VERSION 5.8 ;
BUSBITCHARS "[]" ;
DIVIDERCHAR "/" ;
UNITS
    DATABASE MICRONS 1000 ;
END UNITS

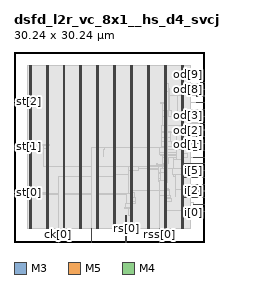
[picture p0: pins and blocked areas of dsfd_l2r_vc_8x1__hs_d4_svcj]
MACRO dsfd_l2r_vc_8x1__hs_d4_svcj
  FOREIGN dsfd_l2r_vc_8x1__hs_d4_svcj 0 0 ;
  CLASS BLOCK ;
  SIZE 30.24 BY 30.24 ;
  PIN ck[0]
    DIRECTION INPUT ;
    USE SIGNAL ;
    PORT
      LAYER M3 ;
        RECT  7.02 0 7.038 0.144 ;
    END
    PORT
      LAYER M3 ;
        RECT  7.02 0.108 7.038 0.52 ;
    END
  END ck[0]
  PIN cks[0]
    DIRECTION INPUT ;
    USE SIGNAL ;
    PORT
      LAYER M5 ;
        RECT  12.384 0 12.408 0.192 ;
    END
    PORT
      LAYER M5 ;
        RECT  12.384 0.144 12.408 2.137 ;
    END
  END cks[0]
  PIN fo[0]
    DIRECTION OUTPUT ;
    USE SIGNAL ;
    PORT
      LAYER M4 ;
        RECT  30.048 4.896 30.24 4.92 ;
    END
    PORT
      LAYER M4 ;
        RECT  27.004 4.896 30.06 4.92 ;
    END
  END fo[0]
  PIN i[0]
    DIRECTION INPUT ;
    USE SIGNAL ;
    PORT
      LAYER M4 ;
        RECT  30.048 5.952 30.24 5.976 ;
    END
    PORT
      LAYER M4 ;
        RECT  28.501 5.952 30.06 5.976 ;
    END
  END i[0]
  PIN i[1]
    DIRECTION INPUT ;
    USE SIGNAL ;
    PORT
      LAYER M4 ;
        RECT  30.048 7.056 30.24 7.08 ;
    END
    PORT
      LAYER M4 ;
        RECT  27.004 7.056 30.06 7.08 ;
    END
  END i[1]
  PIN i[2]
    DIRECTION INPUT ;
    USE SIGNAL ;
    PORT
      LAYER M4 ;
        RECT  30.048 8.112 30.24 8.136 ;
    END
    PORT
      LAYER M4 ;
        RECT  28.501 8.112 30.06 8.136 ;
    END
  END i[2]
  PIN i[3]
    DIRECTION INPUT ;
    USE SIGNAL ;
    PORT
      LAYER M4 ;
        RECT  30.048 9.168 30.24 9.192 ;
    END
    PORT
      LAYER M4 ;
        RECT  28.501 9.168 30.06 9.192 ;
    END
  END i[3]
  PIN i[4]
    DIRECTION INPUT ;
    USE SIGNAL ;
    PORT
      LAYER M4 ;
        RECT  30.048 10.272 30.24 10.296 ;
    END
    PORT
      LAYER M4 ;
        RECT  27.004 10.272 30.06 10.296 ;
    END
  END i[4]
  PIN i[5]
    DIRECTION INPUT ;
    USE SIGNAL ;
    PORT
      LAYER M4 ;
        RECT  30.048 11.376 30.24 11.4 ;
    END
    PORT
      LAYER M4 ;
        RECT  29.653 11.376 30.06 11.4 ;
    END
  END i[5]
  PIN i[6]
    DIRECTION INPUT ;
    USE SIGNAL ;
    PORT
      LAYER M4 ;
        RECT  30.048 12.432 30.24 12.456 ;
    END
    PORT
      LAYER M4 ;
        RECT  27.004 12.432 30.06 12.456 ;
    END
  END i[6]
  PIN i[7]
    DIRECTION INPUT ;
    USE SIGNAL ;
    PORT
      LAYER M4 ;
        RECT  30.048 13.488 30.24 13.512 ;
    END
    PORT
      LAYER M4 ;
        RECT  28.501 13.488 30.06 13.512 ;
    END
  END i[7]
  PIN i[8]
    DIRECTION INPUT ;
    USE SIGNAL ;
    PORT
      LAYER M4 ;
        RECT  30.048 14.592 30.24 14.616 ;
    END
    PORT
      LAYER M4 ;
        RECT  28.501 14.592 30.06 14.616 ;
    END
  END i[8]
  PIN od[0]
    DIRECTION OUTPUT ;
    USE SIGNAL ;
    PORT
      LAYER M4 ;
        RECT  30.048 15.648 30.24 15.672 ;
    END
    PORT
      LAYER M4 ;
        RECT  28.501 15.648 30.06 15.672 ;
    END
  END od[0]
  PIN od[1]
    DIRECTION OUTPUT ;
    USE SIGNAL ;
    PORT
      LAYER M4 ;
        RECT  30.048 16.752 30.24 16.776 ;
    END
    PORT
      LAYER M4 ;
        RECT  29.041 16.752 30.06 16.776 ;
    END
  END od[1]
  PIN od[2]
    DIRECTION OUTPUT ;
    USE SIGNAL ;
    PORT
      LAYER M4 ;
        RECT  30.048 17.808 30.24 17.832 ;
    END
    PORT
      LAYER M4 ;
        RECT  29.653 17.808 30.06 17.832 ;
    END
  END od[2]
  PIN od[3]
    DIRECTION OUTPUT ;
    USE SIGNAL ;
    PORT
      LAYER M4 ;
        RECT  30.048 18.912 30.24 18.936 ;
    END
    PORT
      LAYER M4 ;
        RECT  29.617 18.912 30.06 18.936 ;
    END
  END od[3]
  PIN od[4]
    DIRECTION OUTPUT ;
    USE SIGNAL ;
    PORT
      LAYER M4 ;
        RECT  30.048 19.968 30.24 19.992 ;
    END
    PORT
      LAYER M4 ;
        RECT  29.041 19.968 30.06 19.992 ;
    END
  END od[4]
  PIN od[5]
    DIRECTION OUTPUT ;
    USE SIGNAL ;
    PORT
      LAYER M4 ;
        RECT  30.048 21.072 30.24 21.096 ;
    END
    PORT
      LAYER M4 ;
        RECT  29.617 21.072 30.06 21.096 ;
    END
  END od[5]
  PIN od[6]
    DIRECTION OUTPUT ;
    USE SIGNAL ;
    PORT
      LAYER M4 ;
        RECT  30.048 22.128 30.24 22.152 ;
    END
    PORT
      LAYER M4 ;
        RECT  29.077 22.128 30.06 22.152 ;
    END
  END od[6]
  PIN od[7]
    DIRECTION OUTPUT ;
    USE SIGNAL ;
    PORT
      LAYER M4 ;
        RECT  30.048 23.232 30.24 23.256 ;
    END
    PORT
      LAYER M4 ;
        RECT  29.041 23.232 30.06 23.256 ;
    END
  END od[7]
  PIN od[8]
    DIRECTION OUTPUT ;
    USE SIGNAL ;
    PORT
      LAYER M4 ;
        RECT  30.048 24.288 30.24 24.312 ;
    END
    PORT
      LAYER M4 ;
        RECT  29.653 24.288 30.06 24.312 ;
    END
  END od[8]
  PIN od[9]
    DIRECTION OUTPUT ;
    USE SIGNAL ;
    PORT
      LAYER M4 ;
        RECT  30.048 25.392 30.24 25.416 ;
    END
    PORT
      LAYER M4 ;
        RECT  29.653 25.392 30.06 25.416 ;
    END
  END od[9]
  PIN rs[0]
    DIRECTION INPUT ;
    USE SIGNAL ;
    PORT
      LAYER M3 ;
        RECT  17.82 0 17.838 0.144 ;
    END
    PORT
      LAYER M3 ;
        RECT  17.82 0.108 17.838 4.145 ;
    END
  END rs[0]
  PIN rss[0]
    DIRECTION INPUT ;
    USE SIGNAL ;
    PORT
      LAYER M5 ;
        RECT  23.184 0 23.208 0.192 ;
    END
    PORT
      LAYER M5 ;
        RECT  23.184 0.144 23.208 2.137 ;
    END
  END rss[0]
  PIN st[0]
    DIRECTION OUTPUT ;
    USE SIGNAL ;
    PORT
      LAYER M4 ;
        RECT  0 7.92 0.192 7.944 ;
    END
    PORT
      LAYER M4 ;
        RECT  0.156 7.92 2.408 7.944 ;
    END
  END st[0]
  PIN st[1]
    DIRECTION OUTPUT ;
    USE SIGNAL ;
    PORT
      LAYER M4 ;
        RECT  0 15.12 0.192 15.144 ;
    END
    PORT
      LAYER M4 ;
        RECT  0.156 15.12 2.408 15.144 ;
    END
  END st[1]
  PIN st[2]
    DIRECTION OUTPUT ;
    USE SIGNAL ;
    PORT
      LAYER M4 ;
        RECT  0 22.32 0.192 22.344 ;
    END
    PORT
      LAYER M4 ;
        RECT  0.156 22.32 0.245 22.344 ;
    END
  END st[2]
  PIN VDD
    DIRECTION INOUT ;
    USE POWER ;
    PORT
      LAYER M5 ;
        RECT  26.892 2.151 27.012 28.089 ;
        RECT  24.192 2.151 24.312 28.089 ;
        RECT  21.492 2.151 21.612 28.089 ;
        RECT  18.792 2.151 18.912 28.089 ;
        RECT  16.092 2.151 16.212 28.089 ;
        RECT  13.392 2.151 13.512 28.089 ;
        RECT  10.692 2.151 10.812 28.089 ;
        RECT  7.992 2.151 8.112 28.089 ;
        RECT  5.292 2.151 5.412 28.089 ;
        RECT  2.592 2.151 2.712 28.089 ;
    END
  END VDD
  PIN VSS
    DIRECTION INOUT ;
    USE GROUND ;
    PORT
      LAYER M5 ;
        RECT  26.7 2.137 26.82 28.103 ;
        RECT  24 2.137 24.12 28.103 ;
        RECT  21.3 2.137 21.42 28.103 ;
        RECT  18.6 2.137 18.72 28.103 ;
        RECT  15.9 2.137 16.02 28.103 ;
        RECT  13.2 2.137 13.32 28.103 ;
        RECT  10.5 2.137 10.62 28.103 ;
        RECT  7.8 2.137 7.92 28.103 ;
        RECT  5.1 2.137 5.22 28.103 ;
        RECT  2.4 2.137 2.52 28.103 ;
    END
  END VSS
  # OT_OBS_CLOSED layer=M5 d_um=1.536 added=0
  OBS
    LAYER RVTN ;
     RECT  2.16 2.16 28.08 2.295 ;
     RECT  2.16 2.565 28.08 2.835 ;
     RECT  2.16 3.105 28.08 3.375 ;
     RECT  2.16 3.645 28.08 3.915 ;
     RECT  2.16 4.185 28.08 4.455 ;
     RECT  2.16 4.725 28.08 4.995 ;
     RECT  2.16 5.265 28.08 5.535 ;
     RECT  2.16 5.805 28.08 6.075 ;
     RECT  2.16 6.345 28.08 6.615 ;
     RECT  2.16 6.885 28.08 7.155 ;
     RECT  2.16 7.425 28.08 7.695 ;
     RECT  2.16 7.965 28.08 8.235 ;
     RECT  2.16 8.505 28.08 8.775 ;
     RECT  2.16 9.045 28.08 9.315 ;
     RECT  2.16 9.585 28.08 9.855 ;
     RECT  2.16 10.125 28.08 10.395 ;
     RECT  2.16 10.665 28.08 10.935 ;
     RECT  2.16 11.205 28.08 11.475 ;
     RECT  2.16 11.745 28.08 12.015 ;
     RECT  2.16 12.285 28.08 12.555 ;
     RECT  2.16 12.825 28.08 13.095 ;
     RECT  2.16 13.365 28.08 13.635 ;
     RECT  2.16 13.905 28.08 14.175 ;
     RECT  2.16 14.445 28.08 14.715 ;
     RECT  2.16 14.985 28.08 15.255 ;
     RECT  2.16 15.525 28.08 15.795 ;
     RECT  2.16 16.065 28.08 16.335 ;
     RECT  2.16 16.605 28.08 16.875 ;
     RECT  2.16 17.145 28.08 17.415 ;
     RECT  2.16 17.685 28.08 17.955 ;
     RECT  2.16 18.225 28.08 18.495 ;
     RECT  2.16 18.765 28.08 19.035 ;
     RECT  2.16 19.305 28.08 19.575 ;
     RECT  2.16 19.845 28.08 20.115 ;
     RECT  2.16 20.385 28.08 20.655 ;
     RECT  2.16 20.925 28.08 21.195 ;
     RECT  2.16 21.465 28.08 21.735 ;
     RECT  2.16 22.005 28.08 22.275 ;
     RECT  2.16 22.545 28.08 22.815 ;
     RECT  2.16 23.085 28.08 23.355 ;
     RECT  2.16 23.625 28.08 23.895 ;
     RECT  2.16 24.165 28.08 24.435 ;
     RECT  2.16 24.705 28.08 24.975 ;
     RECT  2.16 25.245 28.08 25.515 ;
     RECT  2.16 25.785 28.08 26.055 ;
     RECT  2.16 26.325 28.08 26.595 ;
     RECT  2.16 26.865 28.08 27.135 ;
     RECT  2.16 27.405 28.08 27.675 ;
     RECT  2.16 27.945 28.08 28.08 ;
    LAYER RVTP ;
     RECT  2.16 2.295 28.08 2.565 ;
     RECT  2.16 2.835 28.08 3.105 ;
     RECT  2.16 3.375 28.08 3.645 ;
     RECT  2.16 3.915 28.08 4.185 ;
     RECT  2.16 4.455 28.08 4.725 ;
     RECT  2.16 4.995 28.08 5.265 ;
     RECT  2.16 5.535 28.08 5.805 ;
     RECT  2.16 6.075 28.08 6.345 ;
     RECT  2.16 6.615 28.08 6.885 ;
     RECT  2.16 7.155 28.08 7.425 ;
     RECT  2.16 7.695 28.08 7.965 ;
     RECT  2.16 8.235 28.08 8.505 ;
     RECT  2.16 8.775 28.08 9.045 ;
     RECT  2.16 9.315 28.08 9.585 ;
     RECT  2.16 9.855 28.08 10.125 ;
     RECT  2.16 10.395 28.08 10.665 ;
     RECT  2.16 10.935 28.08 11.205 ;
     RECT  2.16 11.475 28.08 11.745 ;
     RECT  2.16 12.015 28.08 12.285 ;
     RECT  2.16 12.555 28.08 12.825 ;
     RECT  2.16 13.095 28.08 13.365 ;
     RECT  2.16 13.635 28.08 13.905 ;
     RECT  2.16 14.175 28.08 14.445 ;
     RECT  2.16 14.715 28.08 14.985 ;
     RECT  2.16 15.255 28.08 15.525 ;
     RECT  2.16 15.795 28.08 16.065 ;
     RECT  2.16 16.335 28.08 16.605 ;
     RECT  2.16 16.875 28.08 17.145 ;
     RECT  2.16 17.415 28.08 17.685 ;
     RECT  2.16 17.955 28.08 18.225 ;
     RECT  2.16 18.495 28.08 18.765 ;
     RECT  2.16 19.035 28.08 19.305 ;
     RECT  2.16 19.575 28.08 19.845 ;
     RECT  2.16 20.115 28.08 20.385 ;
     RECT  2.16 20.655 28.08 20.925 ;
     RECT  2.16 21.195 28.08 21.465 ;
     RECT  2.16 21.735 28.08 22.005 ;
     RECT  2.16 22.275 28.08 22.545 ;
     RECT  2.16 22.815 28.08 23.085 ;
     RECT  2.16 23.355 28.08 23.625 ;
     RECT  2.16 23.895 28.08 24.165 ;
     RECT  2.16 24.435 28.08 24.705 ;
     RECT  2.16 24.975 28.08 25.245 ;
     RECT  2.16 25.515 28.08 25.785 ;
     RECT  2.16 26.055 28.08 26.325 ;
     RECT  2.16 26.595 28.08 26.865 ;
     RECT  2.16 27.135 28.08 27.405 ;
     RECT  2.16 27.675 28.08 27.945 ;
    LAYER M1 ;
     RECT  2.16 2.151 28.08 28.089 ;
    LAYER M2 ;
     RECT  0.211 22.176 2.16 22.194 ;
     RECT  6.943 0.531 7.043 0.549 ;
     RECT  2.16 2.151 28.08 28.089 ;
     RECT  28.08 6.318 28.535 6.336 ;
     RECT  28.08 8.208 28.535 8.226 ;
     RECT  28.08 9.09 28.535 9.108 ;
     RECT  28.08 13.41 28.535 13.428 ;
     RECT  28.08 14.958 28.535 15.624 ;
     RECT  28.08 16.776 29.075 16.794 ;
     RECT  28.08 20.016 29.075 20.034 ;
     RECT  28.08 23.256 29.075 23.274 ;
     RECT  28.08 22.176 29.111 22.194 ;
     RECT  28.08 18.936 29.651 18.954 ;
     RECT  28.08 21.096 29.651 21.114 ;
     RECT  28.08 11.52 29.687 11.538 ;
     RECT  28.08 17.586 29.687 17.604 ;
     RECT  28.08 24.372 29.687 24.39 ;
     RECT  28.08 25.146 29.687 25.164 ;
    LAYER M3 ;
     RECT  6.948 0.52 7.038 0.554 ;
     RECT  6.948 0.554 6.966 0.557 ;
     RECT  2.415 2.143 2.505 2.413 ;
     RECT  5.115 2.143 5.205 2.413 ;
     RECT  7.815 2.143 7.905 2.413 ;
     RECT  10.515 2.143 10.605 2.413 ;
     RECT  13.215 2.143 13.305 2.413 ;
     RECT  15.915 2.143 16.005 2.413 ;
     RECT  18.615 2.143 18.705 2.413 ;
     RECT  21.315 2.143 21.405 2.413 ;
     RECT  24.015 2.143 24.105 2.413 ;
     RECT  26.715 2.143 26.805 2.413 ;
     RECT  18.615 2.413 18.897 4.261 ;
     RECT  26.715 2.413 26.997 5.029 ;
     RECT  26.064 5.029 26.997 5.069 ;
     RECT  18.288 4.261 18.897 5.305 ;
     RECT  17.64 5.305 18.897 5.459 ;
     RECT  17.676 5.459 18.897 6.143 ;
     RECT  17.964 6.143 18.897 6.151 ;
     RECT  17.964 6.151 19.278 6.173 ;
     RECT  26.715 5.069 26.997 6.241 ;
     RECT  26.676 6.241 26.997 6.341 ;
     RECT  28.512 5.947 28.53 6.341 ;
     RECT  24.015 2.413 24.297 6.385 ;
     RECT  18.252 6.173 19.278 6.413 ;
     RECT  24.015 6.385 24.75 6.421 ;
     RECT  24.015 6.421 25.11 6.845 ;
     RECT  26.715 6.341 26.997 7.051 ;
     RECT  24.015 6.845 24.894 7.087 ;
     RECT  18.615 6.413 19.278 7.151 ;
     RECT  27.936 7.051 27.954 7.151 ;
     RECT  26.715 7.051 27.054 7.231 ;
     RECT  23.976 7.087 24.894 7.349 ;
     RECT  26.715 7.231 27.234 7.349 ;
     RECT  23.976 7.349 24.75 7.385 ;
     RECT  23.976 7.385 24.714 7.393 ;
     RECT  23.76 7.393 24.714 7.421 ;
     RECT  5.115 2.413 5.397 7.627 ;
     RECT  2.415 2.413 2.697 7.771 ;
     RECT  4.572 7.627 5.397 7.771 ;
     RECT  18.615 7.151 19.134 7.799 ;
     RECT  4.284 7.771 5.397 7.889 ;
     RECT  18.615 7.799 18.897 7.897 ;
     RECT  4.896 7.889 5.397 7.925 ;
     RECT  2.415 7.771 2.754 7.949 ;
     RECT  18.54 7.897 18.897 7.949 ;
     RECT  23.76 7.421 24.297 8.203 ;
     RECT  28.512 8.107 28.53 8.231 ;
     RECT  23.76 8.203 24.57 8.311 ;
     RECT  25.668 7.321 25.686 8.311 ;
     RECT  26.715 7.349 26.997 8.311 ;
     RECT  23.76 8.311 24.714 8.429 ;
     RECT  25.668 8.311 27.63 8.429 ;
     RECT  23.76 8.429 24.57 8.465 ;
     RECT  26.715 8.429 27.63 8.501 ;
     RECT  23.76 8.465 24.297 9.121 ;
     RECT  28.512 9.085 28.53 9.197 ;
     RECT  23.4 9.121 24.297 9.355 ;
     RECT  23.256 9.355 24.297 9.391 ;
     RECT  23.256 9.391 24.354 9.691 ;
     RECT  23.04 9.691 24.354 10.085 ;
     RECT  27.936 10.267 27.954 10.391 ;
     RECT  15.915 2.413 16.197 10.411 ;
     RECT  25.668 8.429 25.758 10.471 ;
     RECT  15.804 10.411 16.197 10.589 ;
     RECT  25.344 10.471 25.758 10.705 ;
     RECT  15.915 10.589 16.197 10.741 ;
     RECT  25.2 10.705 25.758 10.741 ;
     RECT  26.715 8.501 26.997 10.741 ;
     RECT  15.915 10.741 16.398 10.781 ;
     RECT  23.004 10.201 23.022 10.975 ;
     RECT  23.76 10.085 24.354 10.975 ;
     RECT  21.315 2.413 21.597 11.515 ;
     RECT  23.004 10.975 24.354 11.515 ;
     RECT  29.664 11.371 29.682 11.543 ;
     RECT  19.8 11.419 19.818 11.659 ;
     RECT  21.315 11.515 24.354 11.659 ;
     RECT  25.2 10.741 26.997 11.705 ;
     RECT  19.8 11.659 20.394 11.939 ;
     RECT  20.376 11.939 20.394 11.981 ;
     RECT  21.315 11.659 24.39 12.209 ;
     RECT  22.68 12.209 24.39 12.281 ;
     RECT  23.688 12.281 24.39 12.361 ;
     RECT  22.68 12.281 22.806 12.479 ;
     RECT  22.68 12.479 22.698 12.515 ;
     RECT  23.688 12.361 24.498 12.523 ;
     RECT  27.936 12.427 27.954 12.551 ;
     RECT  25.308 11.705 26.997 13.091 ;
     RECT  23.688 12.523 24.534 13.441 ;
     RECT  25.308 13.091 25.938 13.441 ;
     RECT  26.715 13.091 26.997 13.441 ;
     RECT  28.512 13.405 28.53 13.517 ;
     RECT  23.688 13.441 25.938 13.711 ;
     RECT  23.256 13.711 25.938 13.981 ;
     RECT  26.715 13.441 27.666 14.009 ;
     RECT  23.112 13.981 25.938 14.237 ;
     RECT  14.292 13.531 14.31 14.675 ;
     RECT  23.544 14.237 25.938 14.791 ;
     RECT  26.715 14.009 26.997 14.791 ;
     RECT  5.115 7.925 5.397 14.827 ;
     RECT  14.4 14.791 14.418 15.089 ;
     RECT  2.415 7.949 2.697 15.115 ;
     RECT  2.304 15.115 2.697 15.179 ;
     RECT  23.544 14.791 26.997 15.179 ;
     RECT  4.68 14.827 5.397 15.331 ;
     RECT  4.572 15.331 5.634 15.449 ;
     RECT  5.115 15.449 5.634 15.593 ;
     RECT  28.512 14.587 28.53 15.677 ;
     RECT  23.544 15.179 25.074 15.989 ;
     RECT  23.544 15.989 24.93 16.645 ;
     RECT  29.052 16.747 29.07 16.799 ;
     RECT  23.436 16.645 24.93 17.491 ;
     RECT  25.884 15.179 26.997 17.491 ;
     RECT  23.436 17.491 26.997 17.609 ;
     RECT  29.664 17.581 29.682 17.837 ;
     RECT  23.544 17.609 26.997 18.563 ;
     RECT  29.628 18.907 29.646 18.959 ;
     RECT  23.58 18.563 26.997 19.913 ;
     RECT  26.064 19.913 26.997 19.921 ;
     RECT  29.052 19.963 29.07 20.039 ;
     RECT  26.064 19.921 27.306 20.075 ;
     RECT  23.58 19.913 25.11 20.957 ;
     RECT  29.628 21.067 29.646 21.119 ;
     RECT  23.58 20.957 24.786 22.027 ;
     RECT  23.256 22.027 24.786 22.199 ;
     RECT  29.088 22.123 29.106 22.199 ;
     RECT  23.256 22.199 23.274 22.235 ;
     RECT  0.216 22.171 0.234 22.349 ;
     RECT  26.064 20.075 26.997 23.279 ;
     RECT  29.052 23.227 29.07 23.279 ;
     RECT  25.884 23.317 25.902 23.357 ;
     RECT  24.015 22.199 24.786 24.359 ;
     RECT  29.664 24.283 29.682 24.395 ;
     RECT  24.015 24.359 24.606 24.509 ;
     RECT  24.015 24.509 24.57 25.169 ;
     RECT  29.664 25.141 29.682 25.421 ;
     RECT  2.415 15.179 2.697 27.827 ;
     RECT  5.115 15.593 5.397 27.827 ;
     RECT  7.815 2.413 8.097 27.827 ;
     RECT  10.515 2.413 10.797 27.827 ;
     RECT  13.215 2.413 13.497 27.827 ;
     RECT  15.915 10.781 16.197 27.827 ;
     RECT  18.615 7.949 18.897 27.827 ;
     RECT  21.315 12.209 21.597 27.827 ;
     RECT  24.015 25.169 24.297 27.827 ;
     RECT  26.715 23.279 26.997 27.827 ;
     RECT  2.415 27.827 2.505 28.097 ;
     RECT  5.115 27.827 5.205 28.097 ;
     RECT  7.815 27.827 7.905 28.097 ;
     RECT  10.515 27.827 10.605 28.097 ;
     RECT  13.215 27.827 13.305 28.097 ;
     RECT  15.915 27.827 16.005 28.097 ;
     RECT  18.615 27.827 18.705 28.097 ;
     RECT  21.315 27.827 21.405 28.097 ;
     RECT  24.015 27.827 24.105 28.097 ;
     RECT  26.715 27.827 26.805 28.097 ;
    LAYER M4 ;
     RECT  2.408 2.148 2.512 28.092 ;
     RECT  2.512 2.418 2.704 27.822 ;
     RECT  2.704 7.92 2.765 7.944 ;
     RECT  4.561 7.632 5.108 7.656 ;
     RECT  4.693 11.952 5.108 11.976 ;
     RECT  4.669 14.832 5.108 14.856 ;
     RECT  5.108 2.148 5.212 28.092 ;
     RECT  5.212 2.418 5.404 27.822 ;
     RECT  6.937 0.528 7.091 0.552 ;
     RECT  5.404 7.632 7.808 7.656 ;
     RECT  7.045 10.416 7.808 10.44 ;
     RECT  5.404 11.952 7.808 11.976 ;
     RECT  7.808 2.148 7.912 28.092 ;
     RECT  7.912 2.418 8.104 27.822 ;
     RECT  8.104 7.632 10.508 7.656 ;
     RECT  8.104 10.416 10.508 10.44 ;
     RECT  8.104 11.952 10.508 11.976 ;
     RECT  10.508 2.148 10.612 28.092 ;
     RECT  10.612 2.418 10.804 27.822 ;
     RECT  10.804 7.632 13.208 7.656 ;
     RECT  10.804 10.416 13.208 10.44 ;
     RECT  10.804 11.952 13.208 11.976 ;
     RECT  12.373 14.976 13.208 15 ;
     RECT  13.208 2.148 13.312 28.092 ;
     RECT  13.312 2.418 13.504 27.822 ;
     RECT  13.504 7.632 15.908 7.656 ;
     RECT  13.504 10.416 15.908 10.44 ;
     RECT  13.504 11.952 15.908 11.976 ;
     RECT  13.504 14.976 15.908 15 ;
     RECT  15.908 2.148 16.012 28.092 ;
     RECT  16.012 2.418 16.204 27.822 ;
     RECT  16.204 7.632 18.229 7.656 ;
     RECT  16.204 10.752 18.229 10.776 ;
     RECT  16.204 11.952 18.229 11.976 ;
     RECT  17.941 6.144 18.608 6.168 ;
     RECT  18.229 7.632 18.608 7.944 ;
     RECT  18.229 10.752 18.608 11.976 ;
     RECT  16.204 14.976 18.608 15 ;
     RECT  18.608 2.148 18.712 28.092 ;
     RECT  18.712 2.418 18.904 27.822 ;
     RECT  18.904 11.424 19.829 11.976 ;
     RECT  18.904 8.208 21.308 8.232 ;
     RECT  19.829 11.664 21.308 11.976 ;
     RECT  18.904 14.976 21.308 15 ;
     RECT  21.308 2.148 21.412 28.092 ;
     RECT  21.412 2.418 21.604 27.822 ;
     RECT  21.604 11.664 23.065 11.976 ;
     RECT  21.604 14.976 23.101 15 ;
     RECT  23.029 9.696 23.245 9.72 ;
     RECT  23.101 14.208 23.893 15 ;
     RECT  23.605 5.04 24.008 5.064 ;
     RECT  21.604 8.208 24.008 8.232 ;
     RECT  23.245 9.648 24.008 9.72 ;
     RECT  23.065 11.136 24.008 11.976 ;
     RECT  23.893 14.208 24.008 15.432 ;
     RECT  23.245 22.032 24.008 22.056 ;
     RECT  24.008 2.148 24.112 28.092 ;
     RECT  24.112 2.418 24.304 27.822 ;
     RECT  24.304 11.136 24.467 11.688 ;
     RECT  24.304 14.208 24.508 15.192 ;
     RECT  24.508 14.208 24.545 14.232 ;
     RECT  24.304 23.328 24.611 25.224 ;
     RECT  24.304 20.016 24.617 21 ;
     RECT  24.611 23.328 24.652 24.504 ;
     RECT  24.304 22.032 24.659 22.056 ;
     RECT  24.652 23.328 24.661 23.976 ;
     RECT  24.617 20.976 24.7 21 ;
     RECT  24.304 7.392 24.707 8.232 ;
     RECT  24.707 7.392 24.748 7.416 ;
     RECT  24.467 11.664 25.229 11.688 ;
     RECT  24.304 5.04 26.708 5.064 ;
     RECT  24.661 23.328 26.708 23.352 ;
     RECT  26.708 2.148 26.812 28.092 ;
     RECT  26.812 2.418 27.004 27.822 ;
    LAYER M5 ;
     RECT  7.056 0.517 7.08 2.137 ;
     RECT  2.4 2.137 2.52 2.151 ;
     RECT  5.1 2.137 5.22 2.151 ;
     RECT  7.056 2.137 7.92 2.151 ;
     RECT  10.5 2.137 10.62 2.151 ;
     RECT  12.384 2.137 13.32 2.151 ;
     RECT  15.9 2.137 16.02 2.151 ;
     RECT  18.6 2.137 18.72 2.151 ;
     RECT  21.3 2.137 21.42 2.151 ;
     RECT  23.184 2.137 24.12 2.151 ;
     RECT  26.7 2.137 26.82 2.151 ;
     RECT  18.6 2.151 18.912 6.133 ;
     RECT  23.184 2.151 24.312 7.381 ;
     RECT  17.952 6.133 18.912 7.667 ;
     RECT  23.184 7.381 24.696 8.243 ;
     RECT  23.184 8.243 24.312 9.731 ;
     RECT  7.056 2.151 8.112 10.451 ;
     RECT  23.28 9.731 24.312 11.125 ;
     RECT  18.24 7.667 18.912 11.459 ;
     RECT  23.28 11.125 24.456 11.699 ;
     RECT  5.1 2.151 5.412 11.941 ;
     RECT  23.616 11.699 24.456 11.987 ;
     RECT  4.704 11.941 5.412 14.867 ;
     RECT  12.384 2.151 13.512 15.011 ;
     RECT  23.904 11.987 24.456 15.443 ;
     RECT  24 15.443 24.456 20.965 ;
     RECT  24 20.965 24.648 23.987 ;
     RECT  24 23.987 24.6 25.235 ;
     RECT  2.4 2.151 2.712 28.089 ;
     RECT  5.1 14.867 5.412 28.089 ;
     RECT  7.8 10.451 8.112 28.089 ;
     RECT  10.5 2.151 10.812 28.089 ;
     RECT  13.2 15.011 13.512 28.089 ;
     RECT  15.9 2.151 16.212 28.089 ;
     RECT  18.6 11.459 18.912 28.089 ;
     RECT  21.3 2.151 21.612 28.089 ;
     RECT  24 25.235 24.312 28.089 ;
     RECT  26.7 2.151 27.012 28.089 ;
     RECT  2.4 28.089 2.52 28.103 ;
     RECT  5.1 28.089 5.22 28.103 ;
     RECT  7.8 28.089 7.92 28.103 ;
     RECT  10.5 28.089 10.62 28.103 ;
     RECT  13.2 28.089 13.32 28.103 ;
     RECT  15.9 28.089 16.02 28.103 ;
     RECT  18.6 28.089 18.72 28.103 ;
     RECT  21.3 28.089 21.42 28.103 ;
     RECT  24 28.089 24.12 28.103 ;
     RECT  26.7 28.089 26.82 28.103 ;
  END
END dsfd_l2r_vc_8x1__hs_d4_svcj
END LIBRARY
